VERSION 5.7 ;
  NOWIREEXTENSIONATPIN ON ;
  DIVIDERCHAR "/" ;
  BUSBITCHARS "[]" ;
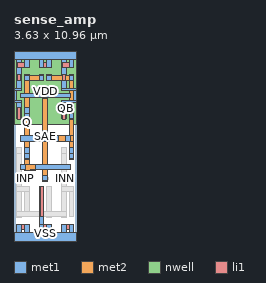
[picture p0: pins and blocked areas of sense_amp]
MACRO sense_amp
  CLASS BLOCK ;
  FOREIGN sense_amp ;
  ORIGIN 0.030 0.000 ;
  SIZE 3.630 BY 10.960 ;
  PIN SAE
    DIRECTION INPUT ;
    USE SIGNAL ;
    ANTENNAGATEAREA 0.525000 ;
    PORT
      LAYER met1 ;
        RECT 1.640 8.520 1.900 8.540 ;
        RECT 0.350 8.250 3.220 8.520 ;
        RECT 1.640 8.220 1.900 8.250 ;
        RECT 1.640 3.760 1.900 3.780 ;
        RECT 1.640 3.460 1.920 3.760 ;
        RECT 1.650 3.450 1.920 3.460 ;
      LAYER met2 ;
        RECT 1.640 8.520 1.900 8.540 ;
        RECT 1.640 3.490 1.910 8.520 ;
        RECT 1.640 3.460 1.900 3.490 ;
    END
  END SAE
  PIN INP
    DIRECTION INPUT ;
    USE SIGNAL ;
    ANTENNAGATEAREA 0.300000 ;
    PORT
      LAYER met1 ;
        RECT 0.350 3.460 0.640 3.750 ;
    END
  END INP
  PIN INN
    DIRECTION INPUT ;
    USE SIGNAL ;
    ANTENNAGATEAREA 0.300000 ;
    PORT
      LAYER met1 ;
        RECT 2.930 3.460 3.220 3.750 ;
    END
  END INN
  PIN Q
    DIRECTION OUTPUT ;
    USE SIGNAL ;
    ANTENNAGATEAREA 0.300000 ;
    ANTENNADIFFAREA 0.810000 ;
    PORT
      LAYER met1 ;
        RECT 0.580 9.560 0.850 9.580 ;
        RECT 1.430 9.560 1.700 9.580 ;
        RECT 0.570 9.270 0.850 9.560 ;
        RECT 1.420 9.270 1.700 9.560 ;
        RECT 0.570 9.240 0.830 9.270 ;
        RECT 1.420 9.240 1.680 9.270 ;
        RECT 0.580 7.340 0.850 7.700 ;
        RECT 0.570 7.050 0.850 7.340 ;
        RECT 0.570 7.020 0.830 7.050 ;
        RECT 2.940 5.750 3.210 6.060 ;
        RECT 0.580 5.040 0.850 5.400 ;
        RECT 0.570 4.750 0.850 5.040 ;
        RECT 0.570 4.720 0.830 4.750 ;
        RECT 0.940 4.100 3.210 4.410 ;
        RECT 0.940 4.090 1.200 4.100 ;
      LAYER met2 ;
        RECT 0.570 9.540 0.830 9.560 ;
        RECT 1.420 9.540 1.680 9.560 ;
        RECT 0.570 9.270 1.690 9.540 ;
        RECT 0.570 4.410 0.840 9.270 ;
        RECT 1.420 9.240 1.680 9.270 ;
        RECT 0.570 4.090 1.210 4.410 ;
    END
  END Q
  PIN QB
    DIRECTION OUTPUT ;
    USE SIGNAL ;
    ANTENNAGATEAREA 0.300000 ;
    ANTENNADIFFAREA 0.810000 ;
    PORT
      LAYER met1 ;
        RECT 1.870 9.560 2.140 9.580 ;
        RECT 3.160 9.560 3.430 9.580 ;
        RECT 1.860 9.270 2.140 9.560 ;
        RECT 3.150 9.270 3.430 9.560 ;
        RECT 1.860 9.240 2.120 9.270 ;
        RECT 3.150 9.240 3.410 9.270 ;
        RECT 3.160 7.340 3.430 7.700 ;
        RECT 3.150 7.050 3.430 7.340 ;
        RECT 3.150 7.020 3.410 7.050 ;
        RECT 0.360 5.750 2.790 6.060 ;
        RECT 2.520 5.740 2.780 5.750 ;
        RECT 3.160 5.040 3.430 5.400 ;
        RECT 3.150 4.750 3.430 5.040 ;
        RECT 3.150 4.720 3.410 4.750 ;
        RECT 0.360 4.100 0.630 4.410 ;
      LAYER met2 ;
        RECT 1.860 9.540 2.120 9.560 ;
        RECT 3.150 9.540 3.410 9.560 ;
        RECT 1.860 9.270 3.420 9.540 ;
        RECT 1.860 9.240 2.120 9.270 ;
        RECT 3.150 6.060 3.420 9.270 ;
        RECT 2.520 5.740 3.420 6.060 ;
        RECT 3.150 4.750 3.420 5.740 ;
        RECT 3.150 4.720 3.410 4.750 ;
    END
  END QB
  PIN VDD
    DIRECTION INOUT ;
    USE POWER ;
    ANTENNADIFFAREA 1.658700 ;
    PORT
      LAYER nwell ;
        RECT -0.030 6.700 3.600 10.540 ;
      LAYER li1 ;
        RECT 0.190 9.990 0.800 10.320 ;
        RECT 1.480 9.990 2.090 10.320 ;
        RECT 2.770 9.990 3.380 10.320 ;
        RECT 0.190 9.260 0.360 9.590 ;
        RECT 2.770 9.260 2.940 9.590 ;
        RECT 0.190 7.030 0.360 7.720 ;
        RECT 2.770 7.030 2.940 7.720 ;
      LAYER met1 ;
        RECT 0.000 10.480 3.570 10.960 ;
        RECT 0.140 8.800 0.410 10.480 ;
        RECT 0.580 10.010 0.850 10.480 ;
        RECT 1.430 10.010 1.700 10.480 ;
        RECT 1.870 10.010 2.140 10.480 ;
        RECT 0.000 8.660 0.410 8.800 ;
        RECT 2.720 8.800 2.990 10.480 ;
        RECT 3.160 10.010 3.430 10.480 ;
        RECT 2.720 8.660 3.570 8.800 ;
        RECT 0.000 8.110 0.140 8.660 ;
        RECT 3.430 8.110 3.570 8.660 ;
        RECT 0.000 7.970 0.410 8.110 ;
        RECT 0.140 7.050 0.410 7.970 ;
        RECT 2.720 7.970 3.570 8.110 ;
        RECT 2.720 7.050 2.990 7.970 ;
    END
  END VDD
  PIN VSS
    DIRECTION INOUT ;
    USE GROUND ;
    ANTENNADIFFAREA 1.388700 ;
    PORT
      LAYER li1 ;
        RECT 1.480 1.390 1.650 3.160 ;
        RECT 0.190 0.640 0.800 0.970 ;
        RECT 1.480 0.640 2.090 0.970 ;
        RECT 2.770 0.640 3.380 0.970 ;
      LAYER met1 ;
        RECT 1.430 1.410 1.700 3.140 ;
        RECT 1.430 0.950 1.660 1.410 ;
        RECT 0.140 0.480 0.410 0.950 ;
        RECT 0.580 0.480 0.850 0.950 ;
        RECT 1.430 0.480 1.700 0.950 ;
        RECT 1.870 0.480 2.140 0.950 ;
        RECT 2.720 0.480 2.990 0.950 ;
        RECT 3.160 0.480 3.430 0.950 ;
        RECT 0.000 0.000 3.570 0.480 ;
    END
  END VSS
  OBS
      LAYER li1 ;
        RECT 0.190 4.730 0.360 5.420 ;
        RECT 2.770 4.730 2.940 5.420 ;
        RECT 0.190 1.390 0.360 3.160 ;
        RECT 0.630 1.390 0.800 3.160 ;
        RECT 1.920 1.390 2.090 3.160 ;
        RECT 2.770 1.390 2.940 3.160 ;
        RECT 3.210 1.390 3.380 3.160 ;
        RECT 0.330 8.300 0.660 8.470 ;
        RECT 1.620 8.300 1.950 8.470 ;
        RECT 2.910 8.300 3.240 8.470 ;
        RECT 1.620 3.520 1.950 3.690 ;
        RECT 0.330 3.520 0.660 3.690 ;
        RECT 2.910 3.520 3.240 3.690 ;
        RECT 0.630 9.260 0.800 9.590 ;
        RECT 1.480 9.260 1.650 9.590 ;
        RECT 0.630 7.030 0.800 7.720 ;
        RECT 2.910 5.820 3.240 5.990 ;
        RECT 0.630 4.730 0.800 5.420 ;
        RECT 2.910 4.170 3.240 4.340 ;
        RECT 1.920 9.260 2.090 9.590 ;
        RECT 3.210 9.260 3.380 9.590 ;
        RECT 3.210 7.030 3.380 7.720 ;
        RECT 0.330 5.820 0.660 5.990 ;
        RECT 3.210 4.730 3.380 5.420 ;
        RECT 0.330 4.170 0.660 4.340 ;
      LAYER met1 ;
        RECT 0.140 5.040 0.410 5.400 ;
        RECT 2.720 5.040 2.990 5.400 ;
        RECT 0.130 4.750 0.410 5.040 ;
        RECT 2.710 4.750 2.990 5.040 ;
        RECT 0.130 4.720 0.390 4.750 ;
        RECT 2.710 4.720 2.970 4.750 ;
        RECT 0.570 3.140 0.830 3.160 ;
        RECT 3.150 3.140 3.410 3.160 ;
        RECT 0.140 1.700 0.410 3.140 ;
        RECT 0.570 2.840 0.850 3.140 ;
        RECT 0.130 1.410 0.410 1.700 ;
        RECT 0.580 1.410 0.850 2.840 ;
        RECT 1.870 1.700 2.140 3.140 ;
        RECT 2.720 1.700 2.990 3.140 ;
        RECT 3.150 2.840 3.430 3.140 ;
        RECT 1.860 1.410 2.140 1.700 ;
        RECT 2.710 1.410 2.990 1.700 ;
        RECT 3.160 1.410 3.430 2.840 ;
        RECT 0.130 1.380 0.390 1.410 ;
        RECT 1.860 1.380 2.120 1.410 ;
        RECT 2.710 1.380 2.970 1.410 ;
      LAYER met2 ;
        RECT 0.130 5.020 0.390 5.040 ;
        RECT 2.710 5.020 2.970 5.040 ;
        RECT 0.130 3.140 0.400 5.020 ;
        RECT 0.570 3.140 0.830 3.160 ;
        RECT 2.710 3.140 2.980 5.020 ;
        RECT 3.150 3.140 3.410 3.160 ;
        RECT 0.130 2.870 0.840 3.140 ;
        RECT 2.710 2.870 3.420 3.140 ;
        RECT 0.570 2.840 0.830 2.870 ;
        RECT 3.150 2.840 3.410 2.870 ;
        RECT 0.130 1.680 0.390 1.700 ;
        RECT 1.860 1.680 2.120 1.700 ;
        RECT 2.710 1.680 2.970 1.700 ;
        RECT 0.130 1.410 2.980 1.680 ;
        RECT 0.130 1.380 0.390 1.410 ;
        RECT 1.860 1.380 2.120 1.410 ;
        RECT 2.710 1.380 2.970 1.410 ;
  END
END sense_amp
END LIBRARY

